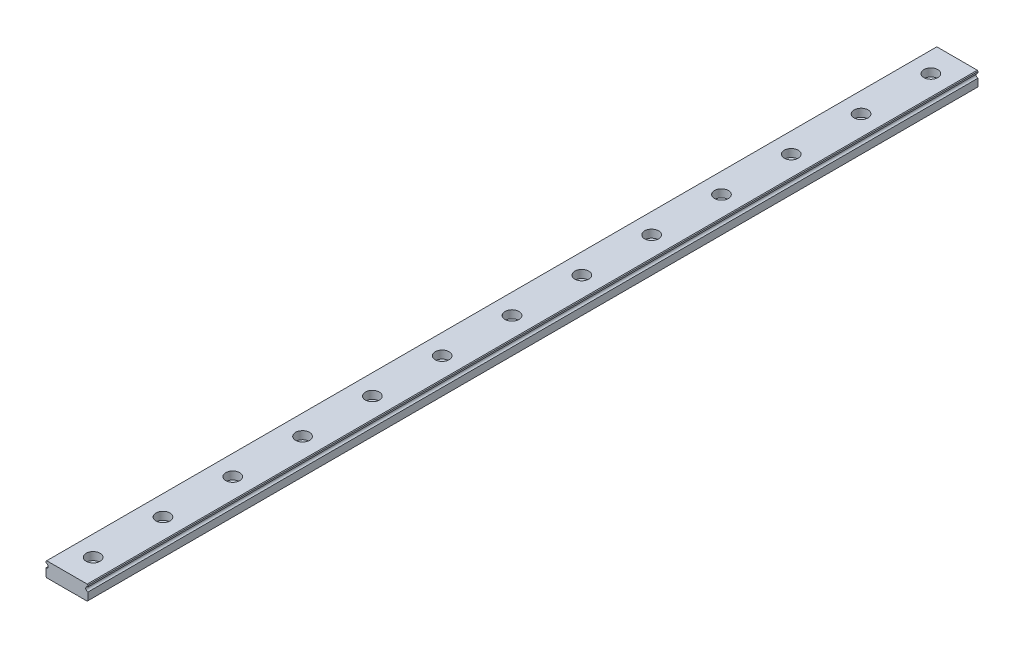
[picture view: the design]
ISO-10303-21;
HEADER;
FILE_DESCRIPTION(('STEP AP214'),'2;1');
FILE_NAME('part.step','',(''),(''),'','','');
FILE_SCHEMA(('AUTOMOTIVE_DESIGN { 1 0 10303 214 1 1 1 1 }'));
ENDSEC;
DATA;
#1=APPLICATION_CONTEXT('core data for automotive mechanical design processes');
#2=APPLICATION_PROTOCOL_DEFINITION('international standard','automotive_design',2000,#1);
#3=PRODUCT_CONTEXT('',#1,'mechanical');
#4=PRODUCT('Part','Part','',(#3));
#5=PRODUCT_RELATED_PRODUCT_CATEGORY('part','',(#4));
#6=PRODUCT_DEFINITION_FORMATION('','',#4);
#7=PRODUCT_DEFINITION_CONTEXT('part definition',#1,'design');
#8=PRODUCT_DEFINITION('design','',#6,#7);
#9=PRODUCT_DEFINITION_SHAPE('','',#8);
#10=(LENGTH_UNIT() NAMED_UNIT(*) SI_UNIT(.MILLI.,.METRE.));
#11=(NAMED_UNIT(*) PLANE_ANGLE_UNIT() SI_UNIT($,.RADIAN.));
#12=(NAMED_UNIT(*) SI_UNIT($,.STERADIAN.) SOLID_ANGLE_UNIT());
#13=UNCERTAINTY_MEASURE_WITH_UNIT(LENGTH_MEASURE(1.E-05),#10,'distance_accuracy_value','');
#14=(GEOMETRIC_REPRESENTATION_CONTEXT(3) GLOBAL_UNCERTAINTY_ASSIGNED_CONTEXT((#13)) GLOBAL_UNIT_ASSIGNED_CONTEXT((#10,
#11,#12)) REPRESENTATION_CONTEXT('',''));
#15=CARTESIAN_POINT('',(0.,0.,0.));
#16=DIRECTION('',(0.,0.,1.));
#17=DIRECTION('',(1.,0.,0.));
#18=AXIS2_PLACEMENT_3D('',#15,#16,#17);
#19=CARTESIAN_POINT('',(-12.,1.75,-510.));
#20=DIRECTION('',(0.,0.,1.));
#21=DIRECTION('',(1.,0.,0.));
#22=AXIS2_PLACEMENT_3D('',#19,#20,#21);
#23=CYLINDRICAL_SURFACE('',#22,1.25);
#24=CARTESIAN_POINT('',(-12.,1.75,0.));
#25=DIRECTION('',(0.,0.,-1.));
#26=DIRECTION('',(1.,0.,0.));
#27=AXIS2_PLACEMENT_3D('',#24,#25,#26);
#28=CIRCLE('',#27,1.25);
#29=CARTESIAN_POINT('',(-12.,3.,0.));
#30=VERTEX_POINT('',#29);
#31=CARTESIAN_POINT('',(-12.,0.5,0.));
#32=VERTEX_POINT('',#31);
#33=EDGE_CURVE('E176',#30,#32,#28,.T.);
#34=ORIENTED_EDGE('',*,*,#33,.F.);
#35=DIRECTION('',(0.,0.,1.));
#36=VECTOR('',#35,1.);
#37=CARTESIAN_POINT('',(-12.,3.,-510.));
#38=LINE('',#37,#36);
#39=CARTESIAN_POINT('',(-12.,3.,-510.));
#40=VERTEX_POINT('',#39);
#41=EDGE_CURVE('E57',#40,#30,#38,.T.);
#42=ORIENTED_EDGE('',*,*,#41,.F.);
#43=CARTESIAN_POINT('',(-12.,1.75,-510.));
#44=DIRECTION('',(0.,0.,-1.));
#45=DIRECTION('',(1.,0.,0.));
#46=AXIS2_PLACEMENT_3D('',#43,#44,#45);
#47=CIRCLE('',#46,1.25);
#48=CARTESIAN_POINT('',(-12.,0.5,-510.));
#49=VERTEX_POINT('',#48);
#50=EDGE_CURVE('E218',#40,#49,#47,.T.);
#51=ORIENTED_EDGE('',*,*,#50,.T.);
#52=DIRECTION('',(0.,0.,1.));
#53=VECTOR('',#52,1.);
#54=CARTESIAN_POINT('',(-12.,0.5,-510.));
#55=LINE('',#54,#53);
#56=EDGE_CURVE('E114',#49,#32,#55,.T.);
#57=ORIENTED_EDGE('',*,*,#56,.T.);
#58=EDGE_LOOP('',(#34,#42,#51,#57));
#59=FACE_BOUND('',#58,.T.);
#60=ADVANCED_FACE('F39',(#59),#23,.F.);
#61=CARTESIAN_POINT('',(-12.,3.,-510.));
#62=DIRECTION('',(-1.,0.,0.));
#63=DIRECTION('',(0.,-1.,0.));
#64=AXIS2_PLACEMENT_3D('',#61,#62,#63);
#65=PLANE('',#64);
#66=DIRECTION('',(0.,-1.,0.));
#67=VECTOR('',#66,1.);
#68=CARTESIAN_POINT('',(-12.,3.,0.));
#69=LINE('',#68,#67);
#70=CARTESIAN_POINT('',(-12.,3.85,0.));
#71=VERTEX_POINT('',#70);
#72=EDGE_CURVE('E214',#71,#30,#69,.T.);
#73=ORIENTED_EDGE('',*,*,#72,.F.);
#74=DIRECTION('',(0.,0.,1.));
#75=VECTOR('',#74,1.);
#76=CARTESIAN_POINT('',(-12.,3.85,-510.));
#77=LINE('',#76,#75);
#78=CARTESIAN_POINT('',(-12.,3.85,-510.));
#79=VERTEX_POINT('',#78);
#80=EDGE_CURVE('E101',#79,#71,#77,.T.);
#81=ORIENTED_EDGE('',*,*,#80,.F.);
#82=DIRECTION('',(0.,-1.,0.));
#83=VECTOR('',#82,1.);
#84=CARTESIAN_POINT('',(-12.,3.,-510.));
#85=LINE('',#84,#83);
#86=EDGE_CURVE('E164',#79,#40,#85,.T.);
#87=ORIENTED_EDGE('',*,*,#86,.T.);
#88=ORIENTED_EDGE('',*,*,#41,.T.);
#89=EDGE_LOOP('',(#73,#81,#87,#88));
#90=FACE_BOUND('',#89,.T.);
#91=ADVANCED_FACE('F395',(#90),#65,.T.);
#92=CARTESIAN_POINT('',(-11.6,4.25,-510.));
#93=DIRECTION('',(-0.707106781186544,0.707106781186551,0.));
#94=DIRECTION('',(-0.707106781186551,-0.707106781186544,0.));
#95=AXIS2_PLACEMENT_3D('',#92,#93,#94);
#96=PLANE('',#95);
#97=DIRECTION('',(-0.707106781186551,-0.707106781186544,0.));
#98=VECTOR('',#97,1.);
#99=CARTESIAN_POINT('',(-11.6,4.25,0.));
#100=LINE('',#99,#98);
#101=CARTESIAN_POINT('',(-11.6,4.25,0.));
#102=VERTEX_POINT('',#101);
#103=EDGE_CURVE('E155',#102,#71,#100,.T.);
#104=ORIENTED_EDGE('',*,*,#103,.F.);
#105=DIRECTION('',(0.,0.,1.));
#106=VECTOR('',#105,1.);
#107=CARTESIAN_POINT('',(-11.6,4.25,-510.));
#108=LINE('',#107,#106);
#109=CARTESIAN_POINT('',(-11.6,4.25,-510.));
#110=VERTEX_POINT('',#109);
#111=EDGE_CURVE('E150',#110,#102,#108,.T.);
#112=ORIENTED_EDGE('',*,*,#111,.F.);
#113=DIRECTION('',(-0.707106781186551,-0.707106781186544,0.));
#114=VECTOR('',#113,1.);
#115=CARTESIAN_POINT('',(-11.6,4.25,-510.));
#116=LINE('',#115,#114);
#117=EDGE_CURVE('E148',#110,#79,#116,.T.);
#118=ORIENTED_EDGE('',*,*,#117,.T.);
#119=ORIENTED_EDGE('',*,*,#80,.T.);
#120=EDGE_LOOP('',(#104,#112,#118,#119));
#121=FACE_BOUND('',#120,.T.);
#122=ADVANCED_FACE('F146',(#121),#96,.T.);
#123=CARTESIAN_POINT('',(11.6,4.25,-510.));
#124=DIRECTION('',(0.,1.,0.));
#125=DIRECTION('',(0.,0.,1.));
#126=AXIS2_PLACEMENT_3D('',#123,#124,#125);
#127=PLANE('',#126);
#128=CARTESIAN_POINT('',(0.,4.25,-55.));
#129=DIRECTION('',(0.,1.,0.));
#130=DIRECTION('',(0.,0.,1.));
#131=AXIS2_PLACEMENT_3D('',#128,#129,#130);
#132=CIRCLE('',#131,4.);
#133=CARTESIAN_POINT('',(0.,4.25,-51.));
#134=VERTEX_POINT('',#133);
#135=EDGE_CURVE('E625',#134,#134,#132,.T.);
#136=ORIENTED_EDGE('',*,*,#135,.F.);
#137=EDGE_LOOP('',(#136));
#138=FACE_BOUND('',#137,.T.);
#139=CARTESIAN_POINT('',(0.,4.25,-15.));
#140=DIRECTION('',(0.,1.,0.));
#141=DIRECTION('',(0.,0.,1.));
#142=AXIS2_PLACEMENT_3D('',#139,#140,#141);
#143=CIRCLE('',#142,4.);
#144=CARTESIAN_POINT('',(0.,4.25,-11.));
#145=VERTEX_POINT('',#144);
#146=EDGE_CURVE('E612',#145,#145,#143,.T.);
#147=ORIENTED_EDGE('',*,*,#146,.F.);
#148=EDGE_LOOP('',(#147));
#149=FACE_BOUND('',#148,.T.);
#150=DIRECTION('',(-1.,0.,0.));
#151=VECTOR('',#150,1.);
#152=CARTESIAN_POINT('',(11.6,4.25,0.));
#153=LINE('',#152,#151);
#154=CARTESIAN_POINT('',(11.6,4.25,0.));
#155=VERTEX_POINT('',#154);
#156=EDGE_CURVE('E208',#155,#102,#153,.T.);
#157=ORIENTED_EDGE('',*,*,#156,.F.);
#158=DIRECTION('',(0.,0.,1.));
#159=VECTOR('',#158,1.);
#160=CARTESIAN_POINT('',(11.6,4.25,-510.));
#161=LINE('',#160,#159);
#162=CARTESIAN_POINT('',(11.6,4.25,-510.));
#163=VERTEX_POINT('',#162);
#164=EDGE_CURVE('E160',#163,#155,#161,.T.);
#165=ORIENTED_EDGE('',*,*,#164,.F.);
#166=DIRECTION('',(-1.,0.,0.));
#167=VECTOR('',#166,1.);
#168=CARTESIAN_POINT('',(11.6,4.25,-510.));
#169=LINE('',#168,#167);
#170=EDGE_CURVE('E161',#163,#110,#169,.T.);
#171=ORIENTED_EDGE('',*,*,#170,.T.);
#172=ORIENTED_EDGE('',*,*,#111,.T.);
#173=EDGE_LOOP('',(#157,#165,#171,#172));
#174=FACE_BOUND('',#173,.T.);
#175=CARTESIAN_POINT('',(0.,4.25,-95.));
#176=DIRECTION('',(0.,1.,0.));
#177=DIRECTION('',(0.,0.,1.));
#178=AXIS2_PLACEMENT_3D('',#175,#176,#177);
#179=CIRCLE('',#178,4.);
#180=CARTESIAN_POINT('',(0.,4.25,-91.));
#181=VERTEX_POINT('',#180);
#182=EDGE_CURVE('E216',#181,#181,#179,.T.);
#183=ORIENTED_EDGE('',*,*,#182,.F.);
#184=EDGE_LOOP('',(#183));
#185=FACE_BOUND('',#184,.T.);
#186=CARTESIAN_POINT('',(0.,4.25,-135.));
#187=DIRECTION('',(0.,1.,0.));
#188=DIRECTION('',(0.,0.,1.));
#189=AXIS2_PLACEMENT_3D('',#186,#187,#188);
#190=CIRCLE('',#189,4.);
#191=CARTESIAN_POINT('',(0.,4.25,-131.));
#192=VERTEX_POINT('',#191);
#193=EDGE_CURVE('E252',#192,#192,#190,.T.);
#194=ORIENTED_EDGE('',*,*,#193,.F.);
#195=EDGE_LOOP('',(#194));
#196=FACE_BOUND('',#195,.T.);
#197=CARTESIAN_POINT('',(0.,4.25,-175.));
#198=DIRECTION('',(0.,1.,0.));
#199=DIRECTION('',(0.,0.,1.));
#200=AXIS2_PLACEMENT_3D('',#197,#198,#199);
#201=CIRCLE('',#200,4.);
#202=CARTESIAN_POINT('',(0.,4.25,-171.));
#203=VERTEX_POINT('',#202);
#204=EDGE_CURVE('E261',#203,#203,#201,.T.);
#205=ORIENTED_EDGE('',*,*,#204,.F.);
#206=EDGE_LOOP('',(#205));
#207=FACE_BOUND('',#206,.T.);
#208=CARTESIAN_POINT('',(0.,4.25,-215.));
#209=DIRECTION('',(0.,1.,0.));
#210=DIRECTION('',(0.,0.,1.));
#211=AXIS2_PLACEMENT_3D('',#208,#209,#210);
#212=CIRCLE('',#211,4.);
#213=CARTESIAN_POINT('',(0.,4.25,-211.));
#214=VERTEX_POINT('',#213);
#215=EDGE_CURVE('E273',#214,#214,#212,.T.);
#216=ORIENTED_EDGE('',*,*,#215,.F.);
#217=EDGE_LOOP('',(#216));
#218=FACE_BOUND('',#217,.T.);
#219=CARTESIAN_POINT('',(0.,4.25,-255.));
#220=DIRECTION('',(0.,1.,0.));
#221=DIRECTION('',(0.,0.,1.));
#222=AXIS2_PLACEMENT_3D('',#219,#220,#221);
#223=CIRCLE('',#222,4.);
#224=CARTESIAN_POINT('',(0.,4.25,-251.));
#225=VERTEX_POINT('',#224);
#226=EDGE_CURVE('E290',#225,#225,#223,.T.);
#227=ORIENTED_EDGE('',*,*,#226,.F.);
#228=EDGE_LOOP('',(#227));
#229=FACE_BOUND('',#228,.T.);
#230=CARTESIAN_POINT('',(0.,4.25,-295.));
#231=DIRECTION('',(0.,1.,0.));
#232=DIRECTION('',(0.,0.,1.));
#233=AXIS2_PLACEMENT_3D('',#230,#231,#232);
#234=CIRCLE('',#233,4.);
#235=CARTESIAN_POINT('',(0.,4.25,-291.));
#236=VERTEX_POINT('',#235);
#237=EDGE_CURVE('E299',#236,#236,#234,.T.);
#238=ORIENTED_EDGE('',*,*,#237,.F.);
#239=EDGE_LOOP('',(#238));
#240=FACE_BOUND('',#239,.T.);
#241=CARTESIAN_POINT('',(0.,4.25,-335.));
#242=DIRECTION('',(0.,1.,0.));
#243=DIRECTION('',(0.,0.,1.));
#244=AXIS2_PLACEMENT_3D('',#241,#242,#243);
#245=CIRCLE('',#244,4.);
#246=CARTESIAN_POINT('',(0.,4.25,-331.));
#247=VERTEX_POINT('',#246);
#248=EDGE_CURVE('E311',#247,#247,#245,.T.);
#249=ORIENTED_EDGE('',*,*,#248,.F.);
#250=EDGE_LOOP('',(#249));
#251=FACE_BOUND('',#250,.T.);
#252=CARTESIAN_POINT('',(0.,4.25,-375.));
#253=DIRECTION('',(0.,1.,0.));
#254=DIRECTION('',(0.,0.,1.));
#255=AXIS2_PLACEMENT_3D('',#252,#253,#254);
#256=CIRCLE('',#255,4.);
#257=CARTESIAN_POINT('',(0.,4.25,-371.));
#258=VERTEX_POINT('',#257);
#259=EDGE_CURVE('E324',#258,#258,#256,.T.);
#260=ORIENTED_EDGE('',*,*,#259,.F.);
#261=EDGE_LOOP('',(#260));
#262=FACE_BOUND('',#261,.T.);
#263=CARTESIAN_POINT('',(0.,4.25,-415.));
#264=DIRECTION('',(0.,1.,0.));
#265=DIRECTION('',(0.,0.,1.));
#266=AXIS2_PLACEMENT_3D('',#263,#264,#265);
#267=CIRCLE('',#266,4.);
#268=CARTESIAN_POINT('',(0.,4.25,-411.));
#269=VERTEX_POINT('',#268);
#270=EDGE_CURVE('E333',#269,#269,#267,.T.);
#271=ORIENTED_EDGE('',*,*,#270,.F.);
#272=EDGE_LOOP('',(#271));
#273=FACE_BOUND('',#272,.T.);
#274=CARTESIAN_POINT('',(0.,4.25,-455.));
#275=DIRECTION('',(0.,1.,0.));
#276=DIRECTION('',(0.,0.,1.));
#277=AXIS2_PLACEMENT_3D('',#274,#275,#276);
#278=CIRCLE('',#277,4.);
#279=CARTESIAN_POINT('',(0.,4.25,-451.));
#280=VERTEX_POINT('',#279);
#281=EDGE_CURVE('E350',#280,#280,#278,.T.);
#282=ORIENTED_EDGE('',*,*,#281,.F.);
#283=EDGE_LOOP('',(#282));
#284=FACE_BOUND('',#283,.T.);
#285=CARTESIAN_POINT('',(0.,4.25,-495.));
#286=DIRECTION('',(0.,1.,0.));
#287=DIRECTION('',(0.,0.,1.));
#288=AXIS2_PLACEMENT_3D('',#285,#286,#287);
#289=CIRCLE('',#288,4.);
#290=CARTESIAN_POINT('',(0.,4.25,-491.));
#291=VERTEX_POINT('',#290);
#292=EDGE_CURVE('E360',#291,#291,#289,.T.);
#293=ORIENTED_EDGE('',*,*,#292,.F.);
#294=EDGE_LOOP('',(#293));
#295=FACE_BOUND('',#294,.T.);
#296=ADVANCED_FACE('F170',(#138,#149,#174,#185,#196,#207,#218,#229,#240,#251,#262,#273,#284,
#295),#127,.T.);
#297=CARTESIAN_POINT('',(12.,3.85,-510.));
#298=DIRECTION('',(0.707106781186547,0.707106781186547,0.));
#299=DIRECTION('',(-0.707106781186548,0.707106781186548,0.));
#300=AXIS2_PLACEMENT_3D('',#297,#298,#299);
#301=PLANE('',#300);
#302=DIRECTION('',(-0.707106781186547,0.707106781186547,0.));
#303=VECTOR('',#302,1.);
#304=CARTESIAN_POINT('',(12.,3.85,0.));
#305=LINE('',#304,#303);
#306=CARTESIAN_POINT('',(12.,3.85,0.));
#307=VERTEX_POINT('',#306);
#308=EDGE_CURVE('E210',#307,#155,#305,.T.);
#309=ORIENTED_EDGE('',*,*,#308,.F.);
#310=DIRECTION('',(0.,0.,1.));
#311=VECTOR('',#310,1.);
#312=CARTESIAN_POINT('',(12.,3.85,-510.));
#313=LINE('',#312,#311);
#314=CARTESIAN_POINT('',(12.,3.85,-510.));
#315=VERTEX_POINT('',#314);
#316=EDGE_CURVE('E222',#315,#307,#313,.T.);
#317=ORIENTED_EDGE('',*,*,#316,.F.);
#318=DIRECTION('',(-0.707106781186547,0.707106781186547,0.));
#319=VECTOR('',#318,1.);
#320=CARTESIAN_POINT('',(12.,3.85,-510.));
#321=LINE('',#320,#319);
#322=EDGE_CURVE('E169',#315,#163,#321,.T.);
#323=ORIENTED_EDGE('',*,*,#322,.T.);
#324=ORIENTED_EDGE('',*,*,#164,.T.);
#325=EDGE_LOOP('',(#309,#317,#323,#324));
#326=FACE_BOUND('',#325,.T.);
#327=ADVANCED_FACE('F379',(#326),#301,.T.);
#328=CARTESIAN_POINT('',(12.,3.85,-510.));
#329=DIRECTION('',(1.,0.,0.));
#330=DIRECTION('',(0.,0.,-1.));
#331=AXIS2_PLACEMENT_3D('',#328,#329,#330);
#332=PLANE('',#331);
#333=DIRECTION('',(0.,1.,0.));
#334=VECTOR('',#333,1.);
#335=CARTESIAN_POINT('',(12.,3.85,0.));
#336=LINE('',#335,#334);
#337=CARTESIAN_POINT('',(12.,3.,0.));
#338=VERTEX_POINT('',#337);
#339=EDGE_CURVE('E201',#338,#307,#336,.T.);
#340=ORIENTED_EDGE('',*,*,#339,.F.);
#341=DIRECTION('',(0.,0.,1.));
#342=VECTOR('',#341,1.);
#343=CARTESIAN_POINT('',(12.,3.,-510.));
#344=LINE('',#343,#342);
#345=CARTESIAN_POINT('',(12.,3.,-510.));
#346=VERTEX_POINT('',#345);
#347=EDGE_CURVE('E224',#346,#338,#344,.T.);
#348=ORIENTED_EDGE('',*,*,#347,.F.);
#349=DIRECTION('',(0.,1.,0.));
#350=VECTOR('',#349,1.);
#351=CARTESIAN_POINT('',(12.,3.85,-510.));
#352=LINE('',#351,#350);
#353=EDGE_CURVE('E171',#346,#315,#352,.T.);
#354=ORIENTED_EDGE('',*,*,#353,.T.);
#355=ORIENTED_EDGE('',*,*,#316,.T.);
#356=EDGE_LOOP('',(#340,#348,#354,#355));
#357=FACE_BOUND('',#356,.T.);
#358=ADVANCED_FACE('F389',(#357),#332,.T.);
#359=CARTESIAN_POINT('',(12.,1.75,-510.));
#360=DIRECTION('',(0.,0.,1.));
#361=DIRECTION('',(1.,0.,0.));
#362=AXIS2_PLACEMENT_3D('',#359,#360,#361);
#363=CYLINDRICAL_SURFACE('',#362,1.25);
#364=CARTESIAN_POINT('',(12.,1.75,0.));
#365=DIRECTION('',(0.,0.,-1.));
#366=DIRECTION('',(1.,0.,0.));
#367=AXIS2_PLACEMENT_3D('',#364,#365,#366);
#368=CIRCLE('',#367,1.25);
#369=CARTESIAN_POINT('',(12.,0.5,0.));
#370=VERTEX_POINT('',#369);
#371=EDGE_CURVE('E202',#370,#338,#368,.T.);
#372=ORIENTED_EDGE('',*,*,#371,.F.);
#373=DIRECTION('',(0.,0.,1.));
#374=VECTOR('',#373,1.);
#375=CARTESIAN_POINT('',(12.,0.5,-510.));
#376=LINE('',#375,#374);
#377=CARTESIAN_POINT('',(12.,0.5,-510.));
#378=VERTEX_POINT('',#377);
#379=EDGE_CURVE('E223',#378,#370,#376,.T.);
#380=ORIENTED_EDGE('',*,*,#379,.F.);
#381=CARTESIAN_POINT('',(12.,1.75,-510.));
#382=DIRECTION('',(0.,0.,-1.));
#383=DIRECTION('',(1.,0.,0.));
#384=AXIS2_PLACEMENT_3D('',#381,#382,#383);
#385=CIRCLE('',#384,1.25);
#386=EDGE_CURVE('E579',#378,#346,#385,.T.);
#387=ORIENTED_EDGE('',*,*,#386,.T.);
#388=ORIENTED_EDGE('',*,*,#347,.T.);
#389=EDGE_LOOP('',(#372,#380,#387,#388));
#390=FACE_BOUND('',#389,.T.);
#391=ADVANCED_FACE('F559',(#390),#363,.F.);
#392=CARTESIAN_POINT('',(12.,0.5,-510.));
#393=DIRECTION('',(1.,0.,0.));
#394=DIRECTION('',(0.,0.,-1.));
#395=AXIS2_PLACEMENT_3D('',#392,#393,#394);
#396=PLANE('',#395);
#397=DIRECTION('',(0.,1.,0.));
#398=VECTOR('',#397,1.);
#399=CARTESIAN_POINT('',(12.,0.5,0.));
#400=LINE('',#399,#398);
#401=CARTESIAN_POINT('',(12.,-3.85,0.));
#402=VERTEX_POINT('',#401);
#403=EDGE_CURVE('E196',#402,#370,#400,.T.);
#404=ORIENTED_EDGE('',*,*,#403,.F.);
#405=DIRECTION('',(0.,0.,1.));
#406=VECTOR('',#405,1.);
#407=CARTESIAN_POINT('',(12.,-3.85,-510.));
#408=LINE('',#407,#406);
#409=CARTESIAN_POINT('',(12.,-3.85,-510.));
#410=VERTEX_POINT('',#409);
#411=EDGE_CURVE('E227',#410,#402,#408,.T.);
#412=ORIENTED_EDGE('',*,*,#411,.F.);
#413=DIRECTION('',(0.,1.,0.));
#414=VECTOR('',#413,1.);
#415=CARTESIAN_POINT('',(12.,0.5,-510.));
#416=LINE('',#415,#414);
#417=EDGE_CURVE('E582',#410,#378,#416,.T.);
#418=ORIENTED_EDGE('',*,*,#417,.T.);
#419=ORIENTED_EDGE('',*,*,#379,.T.);
#420=EDGE_LOOP('',(#404,#412,#418,#419));
#421=FACE_BOUND('',#420,.T.);
#422=ADVANCED_FACE('F554',(#421),#396,.T.);
#423=CARTESIAN_POINT('',(11.6,-4.25,-510.));
#424=DIRECTION('',(0.707106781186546,-0.707106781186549,0.));
#425=DIRECTION('',(0.707106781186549,0.707106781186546,0.));
#426=AXIS2_PLACEMENT_3D('',#423,#424,#425);
#427=PLANE('',#426);
#428=DIRECTION('',(0.707106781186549,0.707106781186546,0.));
#429=VECTOR('',#428,1.);
#430=CARTESIAN_POINT('',(11.6,-4.25,0.));
#431=LINE('',#430,#429);
#432=CARTESIAN_POINT('',(11.6,-4.25,0.));
#433=VERTEX_POINT('',#432);
#434=EDGE_CURVE('E193',#433,#402,#431,.T.);
#435=ORIENTED_EDGE('',*,*,#434,.F.);
#436=DIRECTION('',(0.,0.,1.));
#437=VECTOR('',#436,1.);
#438=CARTESIAN_POINT('',(11.6,-4.25,-510.));
#439=LINE('',#438,#437);
#440=CARTESIAN_POINT('',(11.6,-4.25,-510.));
#441=VERTEX_POINT('',#440);
#442=EDGE_CURVE('E230',#441,#433,#439,.T.);
#443=ORIENTED_EDGE('',*,*,#442,.F.);
#444=DIRECTION('',(0.707106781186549,0.707106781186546,0.));
#445=VECTOR('',#444,1.);
#446=CARTESIAN_POINT('',(11.6,-4.25,-510.));
#447=LINE('',#446,#445);
#448=EDGE_CURVE('E584',#441,#410,#447,.T.);
#449=ORIENTED_EDGE('',*,*,#448,.T.);
#450=ORIENTED_EDGE('',*,*,#411,.T.);
#451=EDGE_LOOP('',(#435,#443,#449,#450));
#452=FACE_BOUND('',#451,.T.);
#453=ADVANCED_FACE('F553',(#452),#427,.T.);
#454=CARTESIAN_POINT('',(11.6,-4.25,-510.));
#455=DIRECTION('',(0.,-1.,0.));
#456=DIRECTION('',(0.,0.,-1.));
#457=AXIS2_PLACEMENT_3D('',#454,#455,#456);
#458=PLANE('',#457);
#459=DIRECTION('',(1.,0.,0.));
#460=VECTOR('',#459,1.);
#461=CARTESIAN_POINT('',(11.6,-4.25,0.));
#462=LINE('',#461,#460);
#463=CARTESIAN_POINT('',(6.3,-4.25,0.));
#464=VERTEX_POINT('',#463);
#465=EDGE_CURVE('E195',#464,#433,#462,.T.);
#466=ORIENTED_EDGE('',*,*,#465,.F.);
#467=DIRECTION('',(0.,0.,1.));
#468=VECTOR('',#467,1.);
#469=CARTESIAN_POINT('',(6.3,-4.25,-510.));
#470=LINE('',#469,#468);
#471=CARTESIAN_POINT('',(6.3,-4.25,-510.));
#472=VERTEX_POINT('',#471);
#473=EDGE_CURVE('E233',#472,#464,#470,.T.);
#474=ORIENTED_EDGE('',*,*,#473,.F.);
#475=DIRECTION('',(1.,0.,0.));
#476=VECTOR('',#475,1.);
#477=CARTESIAN_POINT('',(11.6,-4.25,-510.));
#478=LINE('',#477,#476);
#479=EDGE_CURVE('E586',#472,#441,#478,.T.);
#480=ORIENTED_EDGE('',*,*,#479,.T.);
#481=ORIENTED_EDGE('',*,*,#442,.T.);
#482=EDGE_LOOP('',(#466,#474,#480,#481));
#483=FACE_BOUND('',#482,.T.);
#484=ADVANCED_FACE('F541',(#483),#458,.T.);
#485=CARTESIAN_POINT('',(6.,-4.25,-510.));
#486=DIRECTION('',(0.,0.,1.));
#487=DIRECTION('',(1.,0.,0.));
#488=AXIS2_PLACEMENT_3D('',#485,#486,#487);
#489=CYLINDRICAL_SURFACE('',#488,0.3);
#490=CARTESIAN_POINT('',(6.,-4.25,0.));
#491=DIRECTION('',(0.,0.,-1.));
#492=DIRECTION('',(1.,0.,0.));
#493=AXIS2_PLACEMENT_3D('',#490,#491,#492);
#494=CIRCLE('',#493,0.3);
#495=CARTESIAN_POINT('',(5.7,-4.25,0.));
#496=VERTEX_POINT('',#495);
#497=EDGE_CURVE('E186',#496,#464,#494,.T.);
#498=ORIENTED_EDGE('',*,*,#497,.F.);
#499=DIRECTION('',(0.,0.,1.));
#500=VECTOR('',#499,1.);
#501=CARTESIAN_POINT('',(5.7,-4.25,-510.));
#502=LINE('',#501,#500);
#503=CARTESIAN_POINT('',(5.7,-4.25,-510.));
#504=VERTEX_POINT('',#503);
#505=EDGE_CURVE('E231',#504,#496,#502,.T.);
#506=ORIENTED_EDGE('',*,*,#505,.F.);
#507=CARTESIAN_POINT('',(6.,-4.25,-510.));
#508=DIRECTION('',(0.,0.,-1.));
#509=DIRECTION('',(1.,0.,0.));
#510=AXIS2_PLACEMENT_3D('',#507,#508,#509);
#511=CIRCLE('',#510,0.3);
#512=EDGE_CURVE('E592',#504,#472,#511,.T.);
#513=ORIENTED_EDGE('',*,*,#512,.T.);
#514=ORIENTED_EDGE('',*,*,#473,.T.);
#515=EDGE_LOOP('',(#498,#506,#513,#514));
#516=FACE_BOUND('',#515,.T.);
#517=ADVANCED_FACE('F534',(#516),#489,.F.);
#518=CARTESIAN_POINT('',(5.7,-4.25,-510.));
#519=DIRECTION('',(0.,-1.,0.));
#520=DIRECTION('',(0.,0.,-1.));
#521=AXIS2_PLACEMENT_3D('',#518,#519,#520);
#522=PLANE('',#521);
#523=CARTESIAN_POINT('',(0.,-4.25,-55.));
#524=DIRECTION('',(0.,1.,0.));
#525=DIRECTION('',(0.,0.,1.));
#526=AXIS2_PLACEMENT_3D('',#523,#524,#525);
#527=CIRCLE('',#526,2.25);
#528=CARTESIAN_POINT('',(0.,-4.25,-52.75));
#529=VERTEX_POINT('',#528);
#530=EDGE_CURVE('E619',#529,#529,#527,.T.);
#531=ORIENTED_EDGE('',*,*,#530,.T.);
#532=EDGE_LOOP('',(#531));
#533=FACE_BOUND('',#532,.T.);
#534=CARTESIAN_POINT('',(0.,-4.25,-15.));
#535=DIRECTION('',(0.,1.,0.));
#536=DIRECTION('',(0.,0.,1.));
#537=AXIS2_PLACEMENT_3D('',#534,#535,#536);
#538=CIRCLE('',#537,2.25);
#539=CARTESIAN_POINT('',(0.,-4.25,-12.75));
#540=VERTEX_POINT('',#539);
#541=EDGE_CURVE('E179',#540,#540,#538,.T.);
#542=ORIENTED_EDGE('',*,*,#541,.T.);
#543=EDGE_LOOP('',(#542));
#544=FACE_BOUND('',#543,.T.);
#545=DIRECTION('',(1.,0.,0.));
#546=VECTOR('',#545,1.);
#547=CARTESIAN_POINT('',(5.7,-4.25,0.));
#548=LINE('',#547,#546);
#549=CARTESIAN_POINT('',(-11.6,-4.25,0.));
#550=VERTEX_POINT('',#549);
#551=EDGE_CURVE('E187',#550,#496,#548,.T.);
#552=ORIENTED_EDGE('',*,*,#551,.F.);
#553=DIRECTION('',(0.,0.,1.));
#554=VECTOR('',#553,1.);
#555=CARTESIAN_POINT('',(-11.6,-4.25,-510.));
#556=LINE('',#555,#554);
#557=CARTESIAN_POINT('',(-11.6,-4.25,-510.));
#558=VERTEX_POINT('',#557);
#559=EDGE_CURVE('E232',#558,#550,#556,.T.);
#560=ORIENTED_EDGE('',*,*,#559,.F.);
#561=DIRECTION('',(1.,0.,0.));
#562=VECTOR('',#561,1.);
#563=CARTESIAN_POINT('',(5.7,-4.25,-510.));
#564=LINE('',#563,#562);
#565=EDGE_CURVE('E591',#558,#504,#564,.T.);
#566=ORIENTED_EDGE('',*,*,#565,.T.);
#567=ORIENTED_EDGE('',*,*,#505,.T.);
#568=EDGE_LOOP('',(#552,#560,#566,#567));
#569=FACE_BOUND('',#568,.T.);
#570=CARTESIAN_POINT('',(0.,-4.25,-95.));
#571=DIRECTION('',(0.,1.,0.));
#572=DIRECTION('',(0.,0.,1.));
#573=AXIS2_PLACEMENT_3D('',#570,#571,#572);
#574=CIRCLE('',#573,2.25);
#575=CARTESIAN_POINT('',(0.,-4.25,-92.75));
#576=VERTEX_POINT('',#575);
#577=EDGE_CURVE('E245',#576,#576,#574,.T.);
#578=ORIENTED_EDGE('',*,*,#577,.T.);
#579=EDGE_LOOP('',(#578));
#580=FACE_BOUND('',#579,.T.);
#581=CARTESIAN_POINT('',(0.,-4.25,-135.));
#582=DIRECTION('',(0.,1.,0.));
#583=DIRECTION('',(0.,0.,1.));
#584=AXIS2_PLACEMENT_3D('',#581,#582,#583);
#585=CIRCLE('',#584,2.25);
#586=CARTESIAN_POINT('',(0.,-4.25,-132.75));
#587=VERTEX_POINT('',#586);
#588=EDGE_CURVE('E251',#587,#587,#585,.T.);
#589=ORIENTED_EDGE('',*,*,#588,.T.);
#590=EDGE_LOOP('',(#589));
#591=FACE_BOUND('',#590,.T.);
#592=CARTESIAN_POINT('',(0.,-4.25,-175.));
#593=DIRECTION('',(0.,1.,0.));
#594=DIRECTION('',(0.,0.,1.));
#595=AXIS2_PLACEMENT_3D('',#592,#593,#594);
#596=CIRCLE('',#595,2.25);
#597=CARTESIAN_POINT('',(0.,-4.25,-172.75));
#598=VERTEX_POINT('',#597);
#599=EDGE_CURVE('E267',#598,#598,#596,.T.);
#600=ORIENTED_EDGE('',*,*,#599,.T.);
#601=EDGE_LOOP('',(#600));
#602=FACE_BOUND('',#601,.T.);
#603=CARTESIAN_POINT('',(0.,-4.25,-215.));
#604=DIRECTION('',(0.,1.,0.));
#605=DIRECTION('',(0.,0.,1.));
#606=AXIS2_PLACEMENT_3D('',#603,#604,#605);
#607=CIRCLE('',#606,2.25);
#608=CARTESIAN_POINT('',(0.,-4.25,-212.75));
#609=VERTEX_POINT('',#608);
#610=EDGE_CURVE('E279',#609,#609,#607,.T.);
#611=ORIENTED_EDGE('',*,*,#610,.T.);
#612=EDGE_LOOP('',(#611));
#613=FACE_BOUND('',#612,.T.);
#614=CARTESIAN_POINT('',(0.,-4.25,-255.));
#615=DIRECTION('',(0.,1.,0.));
#616=DIRECTION('',(0.,0.,1.));
#617=AXIS2_PLACEMENT_3D('',#614,#615,#616);
#618=CIRCLE('',#617,2.25);
#619=CARTESIAN_POINT('',(0.,-4.25,-252.75));
#620=VERTEX_POINT('',#619);
#621=EDGE_CURVE('E288',#620,#620,#618,.T.);
#622=ORIENTED_EDGE('',*,*,#621,.T.);
#623=EDGE_LOOP('',(#622));
#624=FACE_BOUND('',#623,.T.);
#625=CARTESIAN_POINT('',(0.,-4.25,-295.));
#626=DIRECTION('',(0.,1.,0.));
#627=DIRECTION('',(0.,0.,1.));
#628=AXIS2_PLACEMENT_3D('',#625,#626,#627);
#629=CIRCLE('',#628,2.25);
#630=CARTESIAN_POINT('',(0.,-4.25,-292.75));
#631=VERTEX_POINT('',#630);
#632=EDGE_CURVE('E305',#631,#631,#629,.T.);
#633=ORIENTED_EDGE('',*,*,#632,.T.);
#634=EDGE_LOOP('',(#633));
#635=FACE_BOUND('',#634,.T.);
#636=CARTESIAN_POINT('',(0.,-4.25,-335.));
#637=DIRECTION('',(0.,1.,0.));
#638=DIRECTION('',(0.,0.,1.));
#639=AXIS2_PLACEMENT_3D('',#636,#637,#638);
#640=CIRCLE('',#639,2.25);
#641=CARTESIAN_POINT('',(0.,-4.25,-332.75));
#642=VERTEX_POINT('',#641);
#643=EDGE_CURVE('E313',#642,#642,#640,.T.);
#644=ORIENTED_EDGE('',*,*,#643,.T.);
#645=EDGE_LOOP('',(#644));
#646=FACE_BOUND('',#645,.T.);
#647=CARTESIAN_POINT('',(0.,-4.25,-375.));
#648=DIRECTION('',(0.,1.,0.));
#649=DIRECTION('',(0.,0.,1.));
#650=AXIS2_PLACEMENT_3D('',#647,#648,#649);
#651=CIRCLE('',#650,2.25);
#652=CARTESIAN_POINT('',(0.,-4.25,-372.75));
#653=VERTEX_POINT('',#652);
#654=EDGE_CURVE('E328',#653,#653,#651,.T.);
#655=ORIENTED_EDGE('',*,*,#654,.T.);
#656=EDGE_LOOP('',(#655));
#657=FACE_BOUND('',#656,.T.);
#658=CARTESIAN_POINT('',(0.,-4.25,-415.));
#659=DIRECTION('',(0.,1.,0.));
#660=DIRECTION('',(0.,0.,1.));
#661=AXIS2_PLACEMENT_3D('',#658,#659,#660);
#662=CIRCLE('',#661,2.25);
#663=CARTESIAN_POINT('',(0.,-4.25,-412.75));
#664=VERTEX_POINT('',#663);
#665=EDGE_CURVE('E336',#664,#664,#662,.T.);
#666=ORIENTED_EDGE('',*,*,#665,.T.);
#667=EDGE_LOOP('',(#666));
#668=FACE_BOUND('',#667,.T.);
#669=CARTESIAN_POINT('',(0.,-4.25,-455.));
#670=DIRECTION('',(0.,1.,0.));
#671=DIRECTION('',(0.,0.,1.));
#672=AXIS2_PLACEMENT_3D('',#669,#670,#671);
#673=CIRCLE('',#672,2.25);
#674=CARTESIAN_POINT('',(0.,-4.25,-452.75));
#675=VERTEX_POINT('',#674);
#676=EDGE_CURVE('E349',#675,#675,#673,.T.);
#677=ORIENTED_EDGE('',*,*,#676,.T.);
#678=EDGE_LOOP('',(#677));
#679=FACE_BOUND('',#678,.T.);
#680=CARTESIAN_POINT('',(0.,-4.25,-495.));
#681=DIRECTION('',(0.,1.,0.));
#682=DIRECTION('',(0.,0.,1.));
#683=AXIS2_PLACEMENT_3D('',#680,#681,#682);
#684=CIRCLE('',#683,2.25);
#685=CARTESIAN_POINT('',(0.,-4.25,-492.75));
#686=VERTEX_POINT('',#685);
#687=EDGE_CURVE('E365',#686,#686,#684,.T.);
#688=ORIENTED_EDGE('',*,*,#687,.T.);
#689=EDGE_LOOP('',(#688));
#690=FACE_BOUND('',#689,.T.);
#691=ADVANCED_FACE('F535',(#533,#544,#569,#580,#591,#602,#613,#624,#635,#646,#657,#668,#679,
#690),#522,.T.);
#692=CARTESIAN_POINT('',(-12.,-3.85,-510.));
#693=DIRECTION('',(-0.707106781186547,-0.707106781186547,0.));
#694=DIRECTION('',(0.707106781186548,-0.707106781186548,0.));
#695=AXIS2_PLACEMENT_3D('',#692,#693,#694);
#696=PLANE('',#695);
#697=DIRECTION('',(0.707106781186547,-0.707106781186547,0.));
#698=VECTOR('',#697,1.);
#699=CARTESIAN_POINT('',(-12.,-3.85,0.));
#700=LINE('',#699,#698);
#701=CARTESIAN_POINT('',(-12.,-3.85,0.));
#702=VERTEX_POINT('',#701);
#703=EDGE_CURVE('E182',#702,#550,#700,.T.);
#704=ORIENTED_EDGE('',*,*,#703,.F.);
#705=DIRECTION('',(0.,0.,1.));
#706=VECTOR('',#705,1.);
#707=CARTESIAN_POINT('',(-12.,-3.85,-510.));
#708=LINE('',#707,#706);
#709=CARTESIAN_POINT('',(-12.,-3.85,-510.));
#710=VERTEX_POINT('',#709);
#711=EDGE_CURVE('E240',#710,#702,#708,.T.);
#712=ORIENTED_EDGE('',*,*,#711,.F.);
#713=DIRECTION('',(0.707106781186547,-0.707106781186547,0.));
#714=VECTOR('',#713,1.);
#715=CARTESIAN_POINT('',(-12.,-3.85,-510.));
#716=LINE('',#715,#714);
#717=EDGE_CURVE('E600',#710,#558,#716,.T.);
#718=ORIENTED_EDGE('',*,*,#717,.T.);
#719=ORIENTED_EDGE('',*,*,#559,.T.);
#720=EDGE_LOOP('',(#704,#712,#718,#719));
#721=FACE_BOUND('',#720,.T.);
#722=ADVANCED_FACE('F531',(#721),#696,.T.);
#723=CARTESIAN_POINT('',(-12.,-3.85,-510.));
#724=DIRECTION('',(-1.,0.,0.));
#725=DIRECTION('',(0.,0.,1.));
#726=AXIS2_PLACEMENT_3D('',#723,#724,#725);
#727=PLANE('',#726);
#728=DIRECTION('',(0.,-1.,0.));
#729=VECTOR('',#728,1.);
#730=CARTESIAN_POINT('',(-12.,-3.85,0.));
#731=LINE('',#730,#729);
#732=EDGE_CURVE('E177',#32,#702,#731,.T.);
#733=ORIENTED_EDGE('',*,*,#732,.F.);
#734=ORIENTED_EDGE('',*,*,#56,.F.);
#735=DIRECTION('',(0.,-1.,0.));
#736=VECTOR('',#735,1.);
#737=CARTESIAN_POINT('',(-12.,-3.85,-510.));
#738=LINE('',#737,#736);
#739=EDGE_CURVE('E598',#49,#710,#738,.T.);
#740=ORIENTED_EDGE('',*,*,#739,.T.);
#741=ORIENTED_EDGE('',*,*,#711,.T.);
#742=EDGE_LOOP('',(#733,#734,#740,#741));
#743=FACE_BOUND('',#742,.T.);
#744=ADVANCED_FACE('F404',(#743),#727,.T.);
#745=CARTESIAN_POINT('',(-12.,1.75,-510.));
#746=DIRECTION('',(0.,0.,1.));
#747=DIRECTION('',(1.,0.,0.));
#748=AXIS2_PLACEMENT_3D('',#745,#746,#747);
#749=PLANE('',#748);
#750=ORIENTED_EDGE('',*,*,#50,.F.);
#751=ORIENTED_EDGE('',*,*,#86,.F.);
#752=ORIENTED_EDGE('',*,*,#117,.F.);
#753=ORIENTED_EDGE('',*,*,#170,.F.);
#754=ORIENTED_EDGE('',*,*,#322,.F.);
#755=ORIENTED_EDGE('',*,*,#353,.F.);
#756=ORIENTED_EDGE('',*,*,#386,.F.);
#757=ORIENTED_EDGE('',*,*,#417,.F.);
#758=ORIENTED_EDGE('',*,*,#448,.F.);
#759=ORIENTED_EDGE('',*,*,#479,.F.);
#760=ORIENTED_EDGE('',*,*,#512,.F.);
#761=ORIENTED_EDGE('',*,*,#565,.F.);
#762=ORIENTED_EDGE('',*,*,#717,.F.);
#763=ORIENTED_EDGE('',*,*,#739,.F.);
#764=EDGE_LOOP('',(#750,#751,#752,#753,#754,#755,#756,#757,#758,#759,#760,#761,#762,#763));
#765=FACE_BOUND('',#764,.T.);
#766=ADVANCED_FACE('F163',(#765),#749,.F.);
#767=CARTESIAN_POINT('',(-12.,1.75,0.));
#768=DIRECTION('',(0.,0.,1.));
#769=DIRECTION('',(1.,0.,0.));
#770=AXIS2_PLACEMENT_3D('',#767,#768,#769);
#771=PLANE('',#770);
#772=ORIENTED_EDGE('',*,*,#33,.T.);
#773=ORIENTED_EDGE('',*,*,#732,.T.);
#774=ORIENTED_EDGE('',*,*,#703,.T.);
#775=ORIENTED_EDGE('',*,*,#551,.T.);
#776=ORIENTED_EDGE('',*,*,#497,.T.);
#777=ORIENTED_EDGE('',*,*,#465,.T.);
#778=ORIENTED_EDGE('',*,*,#434,.T.);
#779=ORIENTED_EDGE('',*,*,#403,.T.);
#780=ORIENTED_EDGE('',*,*,#371,.T.);
#781=ORIENTED_EDGE('',*,*,#339,.T.);
#782=ORIENTED_EDGE('',*,*,#308,.T.);
#783=ORIENTED_EDGE('',*,*,#156,.T.);
#784=ORIENTED_EDGE('',*,*,#103,.T.);
#785=ORIENTED_EDGE('',*,*,#72,.T.);
#786=EDGE_LOOP('',(#772,#773,#774,#775,#776,#777,#778,#779,#780,#781,#782,#783,#784,#785));
#787=FACE_BOUND('',#786,.T.);
#788=ADVANCED_FACE('F573',(#787),#771,.T.);
#789=CARTESIAN_POINT('',(0.,4.25,-15.));
#790=DIRECTION('',(0.,1.,0.));
#791=DIRECTION('',(0.,0.,1.));
#792=AXIS2_PLACEMENT_3D('',#789,#790,#791);
#793=CYLINDRICAL_SURFACE('',#792,2.25);
#794=ORIENTED_EDGE('',*,*,#541,.F.);
#795=EDGE_LOOP('',(#794));
#796=FACE_BOUND('',#795,.T.);
#797=CARTESIAN_POINT('',(0.,-0.25,-15.));
#798=DIRECTION('',(0.,1.,0.));
#799=DIRECTION('',(0.,0.,1.));
#800=AXIS2_PLACEMENT_3D('',#797,#798,#799);
#801=CIRCLE('',#800,2.25);
#802=CARTESIAN_POINT('',(0.,-0.25,-12.75));
#803=VERTEX_POINT('',#802);
#804=EDGE_CURVE('E603',#803,#803,#801,.T.);
#805=ORIENTED_EDGE('',*,*,#804,.T.);
#806=EDGE_LOOP('',(#805));
#807=FACE_BOUND('',#806,.T.);
#808=ADVANCED_FACE('F643',(#796,#807),#793,.F.);
#809=CARTESIAN_POINT('',(2.25000000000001,-0.25,-15.));
#810=DIRECTION('',(0.,-1.,0.));
#811=DIRECTION('',(0.,0.,-1.));
#812=AXIS2_PLACEMENT_3D('',#809,#810,#811);
#813=PLANE('',#812);
#814=ORIENTED_EDGE('',*,*,#804,.F.);
#815=EDGE_LOOP('',(#814));
#816=FACE_BOUND('',#815,.T.);
#817=CARTESIAN_POINT('',(0.,-0.25,-15.));
#818=DIRECTION('',(0.,1.,0.));
#819=DIRECTION('',(0.,0.,1.));
#820=AXIS2_PLACEMENT_3D('',#817,#818,#819);
#821=CIRCLE('',#820,4.);
#822=CARTESIAN_POINT('',(0.,-0.25,-11.));
#823=VERTEX_POINT('',#822);
#824=EDGE_CURVE('E606',#823,#823,#821,.T.);
#825=ORIENTED_EDGE('',*,*,#824,.T.);
#826=EDGE_LOOP('',(#825));
#827=FACE_BOUND('',#826,.T.);
#828=ADVANCED_FACE('F642',(#816,#827),#813,.F.);
#829=CARTESIAN_POINT('',(0.,4.25,-15.));
#830=DIRECTION('',(0.,1.,0.));
#831=DIRECTION('',(0.,0.,1.));
#832=AXIS2_PLACEMENT_3D('',#829,#830,#831);
#833=CYLINDRICAL_SURFACE('',#832,4.);
#834=ORIENTED_EDGE('',*,*,#824,.F.);
#835=EDGE_LOOP('',(#834));
#836=FACE_BOUND('',#835,.T.);
#837=ORIENTED_EDGE('',*,*,#146,.T.);
#838=EDGE_LOOP('',(#837));
#839=FACE_BOUND('',#838,.T.);
#840=ADVANCED_FACE('F637',(#836,#839),#833,.F.);
#841=CARTESIAN_POINT('',(0.,4.25,-55.));
#842=DIRECTION('',(0.,1.,0.));
#843=DIRECTION('',(0.,0.,1.));
#844=AXIS2_PLACEMENT_3D('',#841,#842,#843);
#845=CYLINDRICAL_SURFACE('',#844,2.25);
#846=ORIENTED_EDGE('',*,*,#530,.F.);
#847=EDGE_LOOP('',(#846));
#848=FACE_BOUND('',#847,.T.);
#849=CARTESIAN_POINT('',(0.,-0.25,-55.));
#850=DIRECTION('',(0.,1.,0.));
#851=DIRECTION('',(0.,0.,1.));
#852=AXIS2_PLACEMENT_3D('',#849,#850,#851);
#853=CIRCLE('',#852,2.25);
#854=CARTESIAN_POINT('',(0.,-0.25,-52.75));
#855=VERTEX_POINT('',#854);
#856=EDGE_CURVE('E611',#855,#855,#853,.T.);
#857=ORIENTED_EDGE('',*,*,#856,.T.);
#858=EDGE_LOOP('',(#857));
#859=FACE_BOUND('',#858,.T.);
#860=ADVANCED_FACE('F635',(#848,#859),#845,.F.);
#861=CARTESIAN_POINT('',(2.25000000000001,-0.25,-55.));
#862=DIRECTION('',(0.,-1.,0.));
#863=DIRECTION('',(0.,0.,-1.));
#864=AXIS2_PLACEMENT_3D('',#861,#862,#863);
#865=PLANE('',#864);
#866=ORIENTED_EDGE('',*,*,#856,.F.);
#867=EDGE_LOOP('',(#866));
#868=FACE_BOUND('',#867,.T.);
#869=CARTESIAN_POINT('',(0.,-0.25,-55.));
#870=DIRECTION('',(0.,1.,0.));
#871=DIRECTION('',(0.,0.,1.));
#872=AXIS2_PLACEMENT_3D('',#869,#870,#871);
#873=CIRCLE('',#872,4.);
#874=CARTESIAN_POINT('',(0.,-0.25,-51.));
#875=VERTEX_POINT('',#874);
#876=EDGE_CURVE('E617',#875,#875,#873,.T.);
#877=ORIENTED_EDGE('',*,*,#876,.T.);
#878=EDGE_LOOP('',(#877));
#879=FACE_BOUND('',#878,.T.);
#880=ADVANCED_FACE('F626',(#868,#879),#865,.F.);
#881=CARTESIAN_POINT('',(0.,4.25,-55.));
#882=DIRECTION('',(0.,1.,0.));
#883=DIRECTION('',(0.,0.,1.));
#884=AXIS2_PLACEMENT_3D('',#881,#882,#883);
#885=CYLINDRICAL_SURFACE('',#884,4.);
#886=ORIENTED_EDGE('',*,*,#876,.F.);
#887=EDGE_LOOP('',(#886));
#888=FACE_BOUND('',#887,.T.);
#889=ORIENTED_EDGE('',*,*,#135,.T.);
#890=EDGE_LOOP('',(#889));
#891=FACE_BOUND('',#890,.T.);
#892=ADVANCED_FACE('F419',(#888,#891),#885,.F.);
#893=CARTESIAN_POINT('',(0.,4.25,-95.));
#894=DIRECTION('',(0.,1.,0.));
#895=DIRECTION('',(0.,0.,1.));
#896=AXIS2_PLACEMENT_3D('',#893,#894,#895);
#897=CYLINDRICAL_SURFACE('',#896,4.);
#898=CARTESIAN_POINT('',(0.,-0.25,-95.));
#899=DIRECTION('',(0.,1.,0.));
#900=DIRECTION('',(0.,0.,1.));
#901=AXIS2_PLACEMENT_3D('',#898,#899,#900);
#902=CIRCLE('',#901,4.);
#903=CARTESIAN_POINT('',(0.,-0.25,-91.));
#904=VERTEX_POINT('',#903);
#905=EDGE_CURVE('E247',#904,#904,#902,.T.);
#906=ORIENTED_EDGE('',*,*,#905,.F.);
#907=EDGE_LOOP('',(#906));
#908=FACE_BOUND('',#907,.T.);
#909=ORIENTED_EDGE('',*,*,#182,.T.);
#910=EDGE_LOOP('',(#909));
#911=FACE_BOUND('',#910,.T.);
#912=ADVANCED_FACE('F412',(#908,#911),#897,.F.);
#913=CARTESIAN_POINT('',(2.25000000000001,-0.25,-95.));
#914=DIRECTION('',(0.,-1.,0.));
#915=DIRECTION('',(0.,0.,-1.));
#916=AXIS2_PLACEMENT_3D('',#913,#914,#915);
#917=PLANE('',#916);
#918=CARTESIAN_POINT('',(0.,-0.25,-95.));
#919=DIRECTION('',(0.,1.,0.));
#920=DIRECTION('',(0.,0.,1.));
#921=AXIS2_PLACEMENT_3D('',#918,#919,#920);
#922=CIRCLE('',#921,2.25);
#923=CARTESIAN_POINT('',(0.,-0.25,-92.75));
#924=VERTEX_POINT('',#923);
#925=EDGE_CURVE('E244',#924,#924,#922,.T.);
#926=ORIENTED_EDGE('',*,*,#925,.F.);
#927=EDGE_LOOP('',(#926));
#928=FACE_BOUND('',#927,.T.);
#929=ORIENTED_EDGE('',*,*,#905,.T.);
#930=EDGE_LOOP('',(#929));
#931=FACE_BOUND('',#930,.T.);
#932=ADVANCED_FACE('F408',(#928,#931),#917,.F.);
#933=CARTESIAN_POINT('',(0.,4.25,-95.));
#934=DIRECTION('',(0.,1.,0.));
#935=DIRECTION('',(0.,0.,1.));
#936=AXIS2_PLACEMENT_3D('',#933,#934,#935);
#937=CYLINDRICAL_SURFACE('',#936,2.25);
#938=ORIENTED_EDGE('',*,*,#577,.F.);
#939=EDGE_LOOP('',(#938));
#940=FACE_BOUND('',#939,.T.);
#941=ORIENTED_EDGE('',*,*,#925,.T.);
#942=EDGE_LOOP('',(#941));
#943=FACE_BOUND('',#942,.T.);
#944=ADVANCED_FACE('F407',(#940,#943),#937,.F.);
#945=CARTESIAN_POINT('',(0.,4.25,-135.));
#946=DIRECTION('',(0.,1.,0.));
#947=DIRECTION('',(0.,0.,1.));
#948=AXIS2_PLACEMENT_3D('',#945,#946,#947);
#949=CYLINDRICAL_SURFACE('',#948,4.);
#950=CARTESIAN_POINT('',(0.,-0.25,-135.));
#951=DIRECTION('',(0.,1.,0.));
#952=DIRECTION('',(0.,0.,1.));
#953=AXIS2_PLACEMENT_3D('',#950,#951,#952);
#954=CIRCLE('',#953,4.);
#955=CARTESIAN_POINT('',(0.,-0.25,-131.));
#956=VERTEX_POINT('',#955);
#957=EDGE_CURVE('E258',#956,#956,#954,.T.);
#958=ORIENTED_EDGE('',*,*,#957,.F.);
#959=EDGE_LOOP('',(#958));
#960=FACE_BOUND('',#959,.T.);
#961=ORIENTED_EDGE('',*,*,#193,.T.);
#962=EDGE_LOOP('',(#961));
#963=FACE_BOUND('',#962,.T.);
#964=ADVANCED_FACE('F406',(#960,#963),#949,.F.);
#965=CARTESIAN_POINT('',(2.25000000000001,-0.25,-135.));
#966=DIRECTION('',(0.,-1.,0.));
#967=DIRECTION('',(0.,0.,-1.));
#968=AXIS2_PLACEMENT_3D('',#965,#966,#967);
#969=PLANE('',#968);
#970=CARTESIAN_POINT('',(0.,-0.25,-135.));
#971=DIRECTION('',(0.,1.,0.));
#972=DIRECTION('',(0.,0.,1.));
#973=AXIS2_PLACEMENT_3D('',#970,#971,#972);
#974=CIRCLE('',#973,2.25);
#975=CARTESIAN_POINT('',(0.,-0.25,-132.75));
#976=VERTEX_POINT('',#975);
#977=EDGE_CURVE('E260',#976,#976,#974,.T.);
#978=ORIENTED_EDGE('',*,*,#977,.F.);
#979=EDGE_LOOP('',(#978));
#980=FACE_BOUND('',#979,.T.);
#981=ORIENTED_EDGE('',*,*,#957,.T.);
#982=EDGE_LOOP('',(#981));
#983=FACE_BOUND('',#982,.T.);
#984=ADVANCED_FACE('F425',(#980,#983),#969,.F.);
#985=CARTESIAN_POINT('',(0.,4.25,-135.));
#986=DIRECTION('',(0.,1.,0.));
#987=DIRECTION('',(0.,0.,1.));
#988=AXIS2_PLACEMENT_3D('',#985,#986,#987);
#989=CYLINDRICAL_SURFACE('',#988,2.25);
#990=ORIENTED_EDGE('',*,*,#588,.F.);
#991=EDGE_LOOP('',(#990));
#992=FACE_BOUND('',#991,.T.);
#993=ORIENTED_EDGE('',*,*,#977,.T.);
#994=EDGE_LOOP('',(#993));
#995=FACE_BOUND('',#994,.T.);
#996=ADVANCED_FACE('F418',(#992,#995),#989,.F.);
#997=CARTESIAN_POINT('',(0.,4.25,-175.));
#998=DIRECTION('',(0.,1.,0.));
#999=DIRECTION('',(0.,0.,1.));
#1000=AXIS2_PLACEMENT_3D('',#997,#998,#999);
#1001=CYLINDRICAL_SURFACE('',#1000,4.);
#1002=CARTESIAN_POINT('',(0.,-0.25,-175.));
#1003=DIRECTION('',(0.,1.,0.));
#1004=DIRECTION('',(0.,0.,1.));
#1005=AXIS2_PLACEMENT_3D('',#1002,#1003,#1004);
#1006=CIRCLE('',#1005,4.);
#1007=CARTESIAN_POINT('',(0.,-0.25,-171.));
#1008=VERTEX_POINT('',#1007);
#1009=EDGE_CURVE('E275',#1008,#1008,#1006,.T.);
#1010=ORIENTED_EDGE('',*,*,#1009,.F.);
#1011=EDGE_LOOP('',(#1010));
#1012=FACE_BOUND('',#1011,.T.);
#1013=ORIENTED_EDGE('',*,*,#204,.T.);
#1014=EDGE_LOOP('',(#1013));
#1015=FACE_BOUND('',#1014,.T.);
#1016=ADVANCED_FACE('F421',(#1012,#1015),#1001,.F.);
#1017=CARTESIAN_POINT('',(2.25000000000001,-0.25,-175.));
#1018=DIRECTION('',(0.,-1.,0.));
#1019=DIRECTION('',(0.,0.,-1.));
#1020=AXIS2_PLACEMENT_3D('',#1017,#1018,#1019);
#1021=PLANE('',#1020);
#1022=CARTESIAN_POINT('',(0.,-0.25,-175.));
#1023=DIRECTION('',(0.,1.,0.));
#1024=DIRECTION('',(0.,0.,1.));
#1025=AXIS2_PLACEMENT_3D('',#1022,#1023,#1024);
#1026=CIRCLE('',#1025,2.25);
#1027=CARTESIAN_POINT('',(0.,-0.25,-172.75));
#1028=VERTEX_POINT('',#1027);
#1029=EDGE_CURVE('E266',#1028,#1028,#1026,.T.);
#1030=ORIENTED_EDGE('',*,*,#1029,.F.);
#1031=EDGE_LOOP('',(#1030));
#1032=FACE_BOUND('',#1031,.T.);
#1033=ORIENTED_EDGE('',*,*,#1009,.T.);
#1034=EDGE_LOOP('',(#1033));
#1035=FACE_BOUND('',#1034,.T.);
#1036=ADVANCED_FACE('F436',(#1032,#1035),#1021,.F.);
#1037=CARTESIAN_POINT('',(0.,4.25,-175.));
#1038=DIRECTION('',(0.,1.,0.));
#1039=DIRECTION('',(0.,0.,1.));
#1040=AXIS2_PLACEMENT_3D('',#1037,#1038,#1039);
#1041=CYLINDRICAL_SURFACE('',#1040,2.25);
#1042=ORIENTED_EDGE('',*,*,#599,.F.);
#1043=EDGE_LOOP('',(#1042));
#1044=FACE_BOUND('',#1043,.T.);
#1045=ORIENTED_EDGE('',*,*,#1029,.T.);
#1046=EDGE_LOOP('',(#1045));
#1047=FACE_BOUND('',#1046,.T.);
#1048=ADVANCED_FACE('F435',(#1044,#1047),#1041,.F.);
#1049=CARTESIAN_POINT('',(0.,4.25,-215.));
#1050=DIRECTION('',(0.,1.,0.));
#1051=DIRECTION('',(0.,0.,1.));
#1052=AXIS2_PLACEMENT_3D('',#1049,#1050,#1051);
#1053=CYLINDRICAL_SURFACE('',#1052,4.);
#1054=CARTESIAN_POINT('',(0.,-0.25,-215.));
#1055=DIRECTION('',(0.,1.,0.));
#1056=DIRECTION('',(0.,0.,1.));
#1057=AXIS2_PLACEMENT_3D('',#1054,#1055,#1056);
#1058=CIRCLE('',#1057,4.);
#1059=CARTESIAN_POINT('',(0.,-0.25,-211.));
#1060=VERTEX_POINT('',#1059);
#1061=EDGE_CURVE('E282',#1060,#1060,#1058,.T.);
#1062=ORIENTED_EDGE('',*,*,#1061,.F.);
#1063=EDGE_LOOP('',(#1062));
#1064=FACE_BOUND('',#1063,.T.);
#1065=ORIENTED_EDGE('',*,*,#215,.T.);
#1066=EDGE_LOOP('',(#1065));
#1067=FACE_BOUND('',#1066,.T.);
#1068=ADVANCED_FACE('F434',(#1064,#1067),#1053,.F.);
#1069=CARTESIAN_POINT('',(2.25000000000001,-0.25,-215.));
#1070=DIRECTION('',(0.,-1.,0.));
#1071=DIRECTION('',(0.,0.,-1.));
#1072=AXIS2_PLACEMENT_3D('',#1069,#1070,#1071);
#1073=PLANE('',#1072);
#1074=CARTESIAN_POINT('',(0.,-0.25,-215.));
#1075=DIRECTION('',(0.,1.,0.));
#1076=DIRECTION('',(0.,0.,1.));
#1077=AXIS2_PLACEMENT_3D('',#1074,#1075,#1076);
#1078=CIRCLE('',#1077,2.25);
#1079=CARTESIAN_POINT('',(0.,-0.25,-212.75));
#1080=VERTEX_POINT('',#1079);
#1081=EDGE_CURVE('E283',#1080,#1080,#1078,.T.);
#1082=ORIENTED_EDGE('',*,*,#1081,.F.);
#1083=EDGE_LOOP('',(#1082));
#1084=FACE_BOUND('',#1083,.T.);
#1085=ORIENTED_EDGE('',*,*,#1061,.T.);
#1086=EDGE_LOOP('',(#1085));
#1087=FACE_BOUND('',#1086,.T.);
#1088=ADVANCED_FACE('F449',(#1084,#1087),#1073,.F.);
#1089=CARTESIAN_POINT('',(0.,4.25,-215.));
#1090=DIRECTION('',(0.,1.,0.));
#1091=DIRECTION('',(0.,0.,1.));
#1092=AXIS2_PLACEMENT_3D('',#1089,#1090,#1091);
#1093=CYLINDRICAL_SURFACE('',#1092,2.25);
#1094=ORIENTED_EDGE('',*,*,#610,.F.);
#1095=EDGE_LOOP('',(#1094));
#1096=FACE_BOUND('',#1095,.T.);
#1097=ORIENTED_EDGE('',*,*,#1081,.T.);
#1098=EDGE_LOOP('',(#1097));
#1099=FACE_BOUND('',#1098,.T.);
#1100=ADVANCED_FACE('F443',(#1096,#1099),#1093,.F.);
#1101=CARTESIAN_POINT('',(0.,4.25,-255.));
#1102=DIRECTION('',(0.,1.,0.));
#1103=DIRECTION('',(0.,0.,1.));
#1104=AXIS2_PLACEMENT_3D('',#1101,#1102,#1103);
#1105=CYLINDRICAL_SURFACE('',#1104,4.);
#1106=CARTESIAN_POINT('',(0.,-0.25,-255.));
#1107=DIRECTION('',(0.,1.,0.));
#1108=DIRECTION('',(0.,0.,1.));
#1109=AXIS2_PLACEMENT_3D('',#1106,#1107,#1108);
#1110=CIRCLE('',#1109,4.);
#1111=CARTESIAN_POINT('',(0.,-0.25,-251.));
#1112=VERTEX_POINT('',#1111);
#1113=EDGE_CURVE('E298',#1112,#1112,#1110,.T.);
#1114=ORIENTED_EDGE('',*,*,#1113,.F.);
#1115=EDGE_LOOP('',(#1114));
#1116=FACE_BOUND('',#1115,.T.);
#1117=ORIENTED_EDGE('',*,*,#226,.T.);
#1118=EDGE_LOOP('',(#1117));
#1119=FACE_BOUND('',#1118,.T.);
#1120=ADVANCED_FACE('F450',(#1116,#1119),#1105,.F.);
#1121=CARTESIAN_POINT('',(2.25000000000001,-0.25,-255.));
#1122=DIRECTION('',(0.,-1.,0.));
#1123=DIRECTION('',(0.,0.,-1.));
#1124=AXIS2_PLACEMENT_3D('',#1121,#1122,#1123);
#1125=PLANE('',#1124);
#1126=CARTESIAN_POINT('',(0.,-0.25,-255.));
#1127=DIRECTION('',(0.,1.,0.));
#1128=DIRECTION('',(0.,0.,1.));
#1129=AXIS2_PLACEMENT_3D('',#1126,#1127,#1128);
#1130=CIRCLE('',#1129,2.25);
#1131=CARTESIAN_POINT('',(0.,-0.25,-252.75));
#1132=VERTEX_POINT('',#1131);
#1133=EDGE_CURVE('E291',#1132,#1132,#1130,.T.);
#1134=ORIENTED_EDGE('',*,*,#1133,.F.);
#1135=EDGE_LOOP('',(#1134));
#1136=FACE_BOUND('',#1135,.T.);
#1137=ORIENTED_EDGE('',*,*,#1113,.T.);
#1138=EDGE_LOOP('',(#1137));
#1139=FACE_BOUND('',#1138,.T.);
#1140=ADVANCED_FACE('F459',(#1136,#1139),#1125,.F.);
#1141=CARTESIAN_POINT('',(0.,4.25,-255.));
#1142=DIRECTION('',(0.,1.,0.));
#1143=DIRECTION('',(0.,0.,1.));
#1144=AXIS2_PLACEMENT_3D('',#1141,#1142,#1143);
#1145=CYLINDRICAL_SURFACE('',#1144,2.25);
#1146=ORIENTED_EDGE('',*,*,#621,.F.);
#1147=EDGE_LOOP('',(#1146));
#1148=FACE_BOUND('',#1147,.T.);
#1149=ORIENTED_EDGE('',*,*,#1133,.T.);
#1150=EDGE_LOOP('',(#1149));
#1151=FACE_BOUND('',#1150,.T.);
#1152=ADVANCED_FACE('F458',(#1148,#1151),#1145,.F.);
#1153=CARTESIAN_POINT('',(0.,4.25,-295.));
#1154=DIRECTION('',(0.,1.,0.));
#1155=DIRECTION('',(0.,0.,1.));
#1156=AXIS2_PLACEMENT_3D('',#1153,#1154,#1155);
#1157=CYLINDRICAL_SURFACE('',#1156,4.);
#1158=CARTESIAN_POINT('',(0.,-0.25,-295.));
#1159=DIRECTION('',(0.,1.,0.));
#1160=DIRECTION('',(0.,0.,1.));
#1161=AXIS2_PLACEMENT_3D('',#1158,#1159,#1160);
#1162=CIRCLE('',#1161,4.);
#1163=CARTESIAN_POINT('',(0.,-0.25,-291.));
#1164=VERTEX_POINT('',#1163);
#1165=EDGE_CURVE('E308',#1164,#1164,#1162,.T.);
#1166=ORIENTED_EDGE('',*,*,#1165,.F.);
#1167=EDGE_LOOP('',(#1166));
#1168=FACE_BOUND('',#1167,.T.);
#1169=ORIENTED_EDGE('',*,*,#237,.T.);
#1170=EDGE_LOOP('',(#1169));
#1171=FACE_BOUND('',#1170,.T.);
#1172=ADVANCED_FACE('F457',(#1168,#1171),#1157,.F.);
#1173=CARTESIAN_POINT('',(2.25000000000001,-0.25,-295.));
#1174=DIRECTION('',(0.,-1.,0.));
#1175=DIRECTION('',(0.,0.,-1.));
#1176=AXIS2_PLACEMENT_3D('',#1173,#1174,#1175);
#1177=PLANE('',#1176);
#1178=CARTESIAN_POINT('',(0.,-0.25,-295.));
#1179=DIRECTION('',(0.,1.,0.));
#1180=DIRECTION('',(0.,0.,1.));
#1181=AXIS2_PLACEMENT_3D('',#1178,#1179,#1180);
#1182=CIRCLE('',#1181,2.25);
#1183=CARTESIAN_POINT('',(0.,-0.25,-292.75));
#1184=VERTEX_POINT('',#1183);
#1185=EDGE_CURVE('E304',#1184,#1184,#1182,.T.);
#1186=ORIENTED_EDGE('',*,*,#1185,.F.);
#1187=EDGE_LOOP('',(#1186));
#1188=FACE_BOUND('',#1187,.T.);
#1189=ORIENTED_EDGE('',*,*,#1165,.T.);
#1190=EDGE_LOOP('',(#1189));
#1191=FACE_BOUND('',#1190,.T.);
#1192=ADVANCED_FACE('F475',(#1188,#1191),#1177,.F.);
#1193=CARTESIAN_POINT('',(0.,4.25,-295.));
#1194=DIRECTION('',(0.,1.,0.));
#1195=DIRECTION('',(0.,0.,1.));
#1196=AXIS2_PLACEMENT_3D('',#1193,#1194,#1195);
#1197=CYLINDRICAL_SURFACE('',#1196,2.25);
#1198=ORIENTED_EDGE('',*,*,#632,.F.);
#1199=EDGE_LOOP('',(#1198));
#1200=FACE_BOUND('',#1199,.T.);
#1201=ORIENTED_EDGE('',*,*,#1185,.T.);
#1202=EDGE_LOOP('',(#1201));
#1203=FACE_BOUND('',#1202,.T.);
#1204=ADVANCED_FACE('F466',(#1200,#1203),#1197,.F.);
#1205=CARTESIAN_POINT('',(0.,4.25,-335.));
#1206=DIRECTION('',(0.,1.,0.));
#1207=DIRECTION('',(0.,0.,1.));
#1208=AXIS2_PLACEMENT_3D('',#1205,#1206,#1207);
#1209=CYLINDRICAL_SURFACE('',#1208,4.);
#1210=CARTESIAN_POINT('',(0.,-0.25,-335.));
#1211=DIRECTION('',(0.,1.,0.));
#1212=DIRECTION('',(0.,0.,1.));
#1213=AXIS2_PLACEMENT_3D('',#1210,#1211,#1212);
#1214=CIRCLE('',#1213,4.);
#1215=CARTESIAN_POINT('',(0.,-0.25,-331.));
#1216=VERTEX_POINT('',#1215);
#1217=EDGE_CURVE('E318',#1216,#1216,#1214,.T.);
#1218=ORIENTED_EDGE('',*,*,#1217,.F.);
#1219=EDGE_LOOP('',(#1218));
#1220=FACE_BOUND('',#1219,.T.);
#1221=ORIENTED_EDGE('',*,*,#248,.T.);
#1222=EDGE_LOOP('',(#1221));
#1223=FACE_BOUND('',#1222,.T.);
#1224=ADVANCED_FACE('F472',(#1220,#1223),#1209,.F.);
#1225=CARTESIAN_POINT('',(2.25000000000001,-0.25,-335.));
#1226=DIRECTION('',(0.,-1.,0.));
#1227=DIRECTION('',(0.,0.,-1.));
#1228=AXIS2_PLACEMENT_3D('',#1225,#1226,#1227);
#1229=PLANE('',#1228);
#1230=CARTESIAN_POINT('',(0.,-0.25,-335.));
#1231=DIRECTION('',(0.,1.,0.));
#1232=DIRECTION('',(0.,0.,1.));
#1233=AXIS2_PLACEMENT_3D('',#1230,#1231,#1232);
#1234=CIRCLE('',#1233,2.25);
#1235=CARTESIAN_POINT('',(0.,-0.25,-332.75));
#1236=VERTEX_POINT('',#1235);
#1237=EDGE_CURVE('E320',#1236,#1236,#1234,.T.);
#1238=ORIENTED_EDGE('',*,*,#1237,.F.);
#1239=EDGE_LOOP('',(#1238));
#1240=FACE_BOUND('',#1239,.T.);
#1241=ORIENTED_EDGE('',*,*,#1217,.T.);
#1242=EDGE_LOOP('',(#1241));
#1243=FACE_BOUND('',#1242,.T.);
#1244=ADVANCED_FACE('F481',(#1240,#1243),#1229,.F.);
#1245=CARTESIAN_POINT('',(0.,4.25,-335.));
#1246=DIRECTION('',(0.,1.,0.));
#1247=DIRECTION('',(0.,0.,1.));
#1248=AXIS2_PLACEMENT_3D('',#1245,#1246,#1247);
#1249=CYLINDRICAL_SURFACE('',#1248,2.25);
#1250=ORIENTED_EDGE('',*,*,#643,.F.);
#1251=EDGE_LOOP('',(#1250));
#1252=FACE_BOUND('',#1251,.T.);
#1253=ORIENTED_EDGE('',*,*,#1237,.T.);
#1254=EDGE_LOOP('',(#1253));
#1255=FACE_BOUND('',#1254,.T.);
#1256=ADVANCED_FACE('F479',(#1252,#1255),#1249,.F.);
#1257=CARTESIAN_POINT('',(0.,4.25,-375.));
#1258=DIRECTION('',(0.,1.,0.));
#1259=DIRECTION('',(0.,0.,1.));
#1260=AXIS2_PLACEMENT_3D('',#1257,#1258,#1259);
#1261=CYLINDRICAL_SURFACE('',#1260,4.);
#1262=CARTESIAN_POINT('',(0.,-0.25,-375.));
#1263=DIRECTION('',(0.,1.,0.));
#1264=DIRECTION('',(0.,0.,1.));
#1265=AXIS2_PLACEMENT_3D('',#1262,#1263,#1264);
#1266=CIRCLE('',#1265,4.);
#1267=CARTESIAN_POINT('',(0.,-0.25,-371.));
#1268=VERTEX_POINT('',#1267);
#1269=EDGE_CURVE('E335',#1268,#1268,#1266,.T.);
#1270=ORIENTED_EDGE('',*,*,#1269,.F.);
#1271=EDGE_LOOP('',(#1270));
#1272=FACE_BOUND('',#1271,.T.);
#1273=ORIENTED_EDGE('',*,*,#259,.T.);
#1274=EDGE_LOOP('',(#1273));
#1275=FACE_BOUND('',#1274,.T.);
#1276=ADVANCED_FACE('F484',(#1272,#1275),#1261,.F.);
#1277=CARTESIAN_POINT('',(2.25000000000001,-0.25,-375.));
#1278=DIRECTION('',(0.,-1.,0.));
#1279=DIRECTION('',(0.,0.,-1.));
#1280=AXIS2_PLACEMENT_3D('',#1277,#1278,#1279);
#1281=PLANE('',#1280);
#1282=CARTESIAN_POINT('',(0.,-0.25,-375.));
#1283=DIRECTION('',(0.,1.,0.));
#1284=DIRECTION('',(0.,0.,1.));
#1285=AXIS2_PLACEMENT_3D('',#1282,#1283,#1284);
#1286=CIRCLE('',#1285,2.25);
#1287=CARTESIAN_POINT('',(0.,-0.25,-372.75));
#1288=VERTEX_POINT('',#1287);
#1289=EDGE_CURVE('E327',#1288,#1288,#1286,.T.);
#1290=ORIENTED_EDGE('',*,*,#1289,.F.);
#1291=EDGE_LOOP('',(#1290));
#1292=FACE_BOUND('',#1291,.T.);
#1293=ORIENTED_EDGE('',*,*,#1269,.T.);
#1294=EDGE_LOOP('',(#1293));
#1295=FACE_BOUND('',#1294,.T.);
#1296=ADVANCED_FACE('F496',(#1292,#1295),#1281,.F.);
#1297=CARTESIAN_POINT('',(0.,4.25,-375.));
#1298=DIRECTION('',(0.,1.,0.));
#1299=DIRECTION('',(0.,0.,1.));
#1300=AXIS2_PLACEMENT_3D('',#1297,#1298,#1299);
#1301=CYLINDRICAL_SURFACE('',#1300,2.25);
#1302=ORIENTED_EDGE('',*,*,#654,.F.);
#1303=EDGE_LOOP('',(#1302));
#1304=FACE_BOUND('',#1303,.T.);
#1305=ORIENTED_EDGE('',*,*,#1289,.T.);
#1306=EDGE_LOOP('',(#1305));
#1307=FACE_BOUND('',#1306,.T.);
#1308=ADVANCED_FACE('F495',(#1304,#1307),#1301,.F.);
#1309=CARTESIAN_POINT('',(0.,4.25,-415.));
#1310=DIRECTION('',(0.,1.,0.));
#1311=DIRECTION('',(0.,0.,1.));
#1312=AXIS2_PLACEMENT_3D('',#1309,#1310,#1311);
#1313=CYLINDRICAL_SURFACE('',#1312,4.);
#1314=CARTESIAN_POINT('',(0.,-0.25,-415.));
#1315=DIRECTION('',(0.,1.,0.));
#1316=DIRECTION('',(0.,0.,1.));
#1317=AXIS2_PLACEMENT_3D('',#1314,#1315,#1316);
#1318=CIRCLE('',#1317,4.);
#1319=CARTESIAN_POINT('',(0.,-0.25,-411.));
#1320=VERTEX_POINT('',#1319);
#1321=EDGE_CURVE('E341',#1320,#1320,#1318,.T.);
#1322=ORIENTED_EDGE('',*,*,#1321,.F.);
#1323=EDGE_LOOP('',(#1322));
#1324=FACE_BOUND('',#1323,.T.);
#1325=ORIENTED_EDGE('',*,*,#270,.T.);
#1326=EDGE_LOOP('',(#1325));
#1327=FACE_BOUND('',#1326,.T.);
#1328=ADVANCED_FACE('F492',(#1324,#1327),#1313,.F.);
#1329=CARTESIAN_POINT('',(2.25000000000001,-0.25,-415.));
#1330=DIRECTION('',(0.,-1.,0.));
#1331=DIRECTION('',(0.,0.,-1.));
#1332=AXIS2_PLACEMENT_3D('',#1329,#1330,#1331);
#1333=PLANE('',#1332);
#1334=CARTESIAN_POINT('',(0.,-0.25,-415.));
#1335=DIRECTION('',(0.,1.,0.));
#1336=DIRECTION('',(0.,0.,1.));
#1337=AXIS2_PLACEMENT_3D('',#1334,#1335,#1336);
#1338=CIRCLE('',#1337,2.25);
#1339=CARTESIAN_POINT('',(0.,-0.25,-412.75));
#1340=VERTEX_POINT('',#1339);
#1341=EDGE_CURVE('E342',#1340,#1340,#1338,.T.);
#1342=ORIENTED_EDGE('',*,*,#1341,.F.);
#1343=EDGE_LOOP('',(#1342));
#1344=FACE_BOUND('',#1343,.T.);
#1345=ORIENTED_EDGE('',*,*,#1321,.T.);
#1346=EDGE_LOOP('',(#1345));
#1347=FACE_BOUND('',#1346,.T.);
#1348=ADVANCED_FACE('F507',(#1344,#1347),#1333,.F.);
#1349=CARTESIAN_POINT('',(0.,4.25,-415.));
#1350=DIRECTION('',(0.,1.,0.));
#1351=DIRECTION('',(0.,0.,1.));
#1352=AXIS2_PLACEMENT_3D('',#1349,#1350,#1351);
#1353=CYLINDRICAL_SURFACE('',#1352,2.25);
#1354=ORIENTED_EDGE('',*,*,#665,.F.);
#1355=EDGE_LOOP('',(#1354));
#1356=FACE_BOUND('',#1355,.T.);
#1357=ORIENTED_EDGE('',*,*,#1341,.T.);
#1358=EDGE_LOOP('',(#1357));
#1359=FACE_BOUND('',#1358,.T.);
#1360=ADVANCED_FACE('F502',(#1356,#1359),#1353,.F.);
#1361=CARTESIAN_POINT('',(0.,4.25,-455.));
#1362=DIRECTION('',(0.,1.,0.));
#1363=DIRECTION('',(0.,0.,1.));
#1364=AXIS2_PLACEMENT_3D('',#1361,#1362,#1363);
#1365=CYLINDRICAL_SURFACE('',#1364,4.);
#1366=CARTESIAN_POINT('',(0.,-0.25,-455.));
#1367=DIRECTION('',(0.,1.,0.));
#1368=DIRECTION('',(0.,0.,1.));
#1369=AXIS2_PLACEMENT_3D('',#1366,#1367,#1368);
#1370=CIRCLE('',#1369,4.);
#1371=CARTESIAN_POINT('',(0.,-0.25,-451.));
#1372=VERTEX_POINT('',#1371);
#1373=EDGE_CURVE('E358',#1372,#1372,#1370,.T.);
#1374=ORIENTED_EDGE('',*,*,#1373,.F.);
#1375=EDGE_LOOP('',(#1374));
#1376=FACE_BOUND('',#1375,.T.);
#1377=ORIENTED_EDGE('',*,*,#281,.T.);
#1378=EDGE_LOOP('',(#1377));
#1379=FACE_BOUND('',#1378,.T.);
#1380=ADVANCED_FACE('F510',(#1376,#1379),#1365,.F.);
#1381=CARTESIAN_POINT('',(2.25000000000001,-0.25,-455.));
#1382=DIRECTION('',(0.,-1.,0.));
#1383=DIRECTION('',(0.,0.,-1.));
#1384=AXIS2_PLACEMENT_3D('',#1381,#1382,#1383);
#1385=PLANE('',#1384);
#1386=CARTESIAN_POINT('',(0.,-0.25,-455.));
#1387=DIRECTION('',(0.,1.,0.));
#1388=DIRECTION('',(0.,0.,1.));
#1389=AXIS2_PLACEMENT_3D('',#1386,#1387,#1388);
#1390=CIRCLE('',#1389,2.25);
#1391=CARTESIAN_POINT('',(0.,-0.25,-452.75));
#1392=VERTEX_POINT('',#1391);
#1393=EDGE_CURVE('E354',#1392,#1392,#1390,.T.);
#1394=ORIENTED_EDGE('',*,*,#1393,.F.);
#1395=EDGE_LOOP('',(#1394));
#1396=FACE_BOUND('',#1395,.T.);
#1397=ORIENTED_EDGE('',*,*,#1373,.T.);
#1398=EDGE_LOOP('',(#1397));
#1399=FACE_BOUND('',#1398,.T.);
#1400=ADVANCED_FACE('F519',(#1396,#1399),#1385,.F.);
#1401=CARTESIAN_POINT('',(0.,4.25,-455.));
#1402=DIRECTION('',(0.,1.,0.));
#1403=DIRECTION('',(0.,0.,1.));
#1404=AXIS2_PLACEMENT_3D('',#1401,#1402,#1403);
#1405=CYLINDRICAL_SURFACE('',#1404,2.25);
#1406=ORIENTED_EDGE('',*,*,#676,.F.);
#1407=EDGE_LOOP('',(#1406));
#1408=FACE_BOUND('',#1407,.T.);
#1409=ORIENTED_EDGE('',*,*,#1393,.T.);
#1410=EDGE_LOOP('',(#1409));
#1411=FACE_BOUND('',#1410,.T.);
#1412=ADVANCED_FACE('F376',(#1408,#1411),#1405,.F.);
#1413=CARTESIAN_POINT('',(0.,4.25,-495.));
#1414=DIRECTION('',(0.,1.,0.));
#1415=DIRECTION('',(0.,0.,1.));
#1416=AXIS2_PLACEMENT_3D('',#1413,#1414,#1415);
#1417=CYLINDRICAL_SURFACE('',#1416,4.);
#1418=CARTESIAN_POINT('',(0.,-0.25,-495.));
#1419=DIRECTION('',(0.,1.,0.));
#1420=DIRECTION('',(0.,0.,1.));
#1421=AXIS2_PLACEMENT_3D('',#1418,#1419,#1420);
#1422=CIRCLE('',#1421,4.);
#1423=CARTESIAN_POINT('',(0.,-0.25,-491.));
#1424=VERTEX_POINT('',#1423);
#1425=EDGE_CURVE('E11',#1424,#1424,#1422,.T.);
#1426=ORIENTED_EDGE('',*,*,#1425,.F.);
#1427=EDGE_LOOP('',(#1426));
#1428=FACE_BOUND('',#1427,.T.);
#1429=ORIENTED_EDGE('',*,*,#292,.T.);
#1430=EDGE_LOOP('',(#1429));
#1431=FACE_BOUND('',#1430,.T.);
#1432=ADVANCED_FACE('F41',(#1428,#1431),#1417,.F.);
#1433=CARTESIAN_POINT('',(2.25000000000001,-0.25,-495.));
#1434=DIRECTION('',(0.,-1.,0.));
#1435=DIRECTION('',(0.,0.,-1.));
#1436=AXIS2_PLACEMENT_3D('',#1433,#1434,#1435);
#1437=PLANE('',#1436);
#1438=CARTESIAN_POINT('',(0.,-0.25,-495.));
#1439=DIRECTION('',(0.,1.,0.));
#1440=DIRECTION('',(0.,0.,1.));
#1441=AXIS2_PLACEMENT_3D('',#1438,#1439,#1440);
#1442=CIRCLE('',#1441,2.25);
#1443=CARTESIAN_POINT('',(0.,-0.25,-492.75));
#1444=VERTEX_POINT('',#1443);
#1445=EDGE_CURVE('E48',#1444,#1444,#1442,.T.);
#1446=ORIENTED_EDGE('',*,*,#1445,.F.);
#1447=EDGE_LOOP('',(#1446));
#1448=FACE_BOUND('',#1447,.T.);
#1449=ORIENTED_EDGE('',*,*,#1425,.T.);
#1450=EDGE_LOOP('',(#1449));
#1451=FACE_BOUND('',#1450,.T.);
#1452=ADVANCED_FACE('F367',(#1448,#1451),#1437,.F.);
#1453=CARTESIAN_POINT('',(0.,4.25,-495.));
#1454=DIRECTION('',(0.,1.,0.));
#1455=DIRECTION('',(0.,0.,1.));
#1456=AXIS2_PLACEMENT_3D('',#1453,#1454,#1455);
#1457=CYLINDRICAL_SURFACE('',#1456,2.25);
#1458=ORIENTED_EDGE('',*,*,#687,.F.);
#1459=EDGE_LOOP('',(#1458));
#1460=FACE_BOUND('',#1459,.T.);
#1461=ORIENTED_EDGE('',*,*,#1445,.T.);
#1462=EDGE_LOOP('',(#1461));
#1463=FACE_BOUND('',#1462,.T.);
#1464=ADVANCED_FACE('F370',(#1460,#1463),#1457,.F.);
#1465=CLOSED_SHELL('',(#60,#91,#122,#296,#327,#358,#391,#422,#453,#484,#517,#691,#722,#744,#766,
#788,#808,#828,#840,#860,#880,#892,#912,#932,#944,#964,#984,#996,#1016,#1036,#1048,#1068,#1088,
#1100,#1120,#1140,#1152,#1172,#1192,#1204,#1224,#1244,#1256,#1276,#1296,#1308,#1328,#1348,#1360,
#1380,#1400,#1412,#1432,#1452,#1464));
#1466=MANIFOLD_SOLID_BREP('B2',#1465);
#1467=ADVANCED_BREP_SHAPE_REPRESENTATION('',(#18,#1466),#14);
#1468=SHAPE_DEFINITION_REPRESENTATION(#9,#1467);
ENDSEC;
END-ISO-10303-21;
